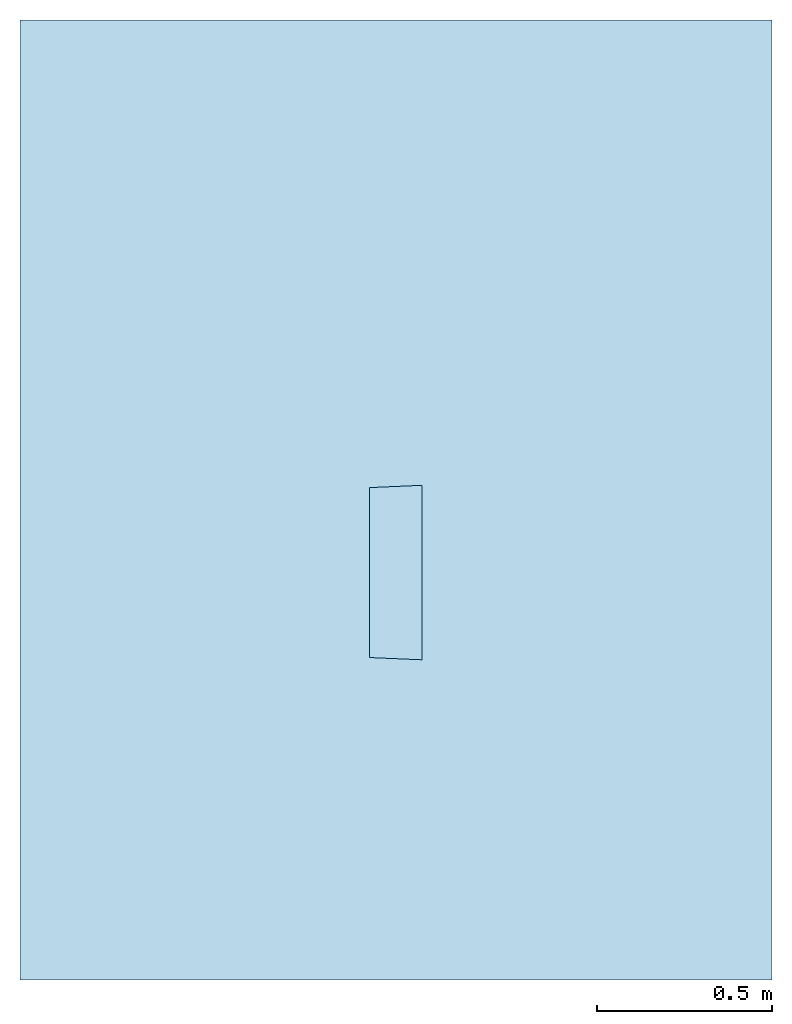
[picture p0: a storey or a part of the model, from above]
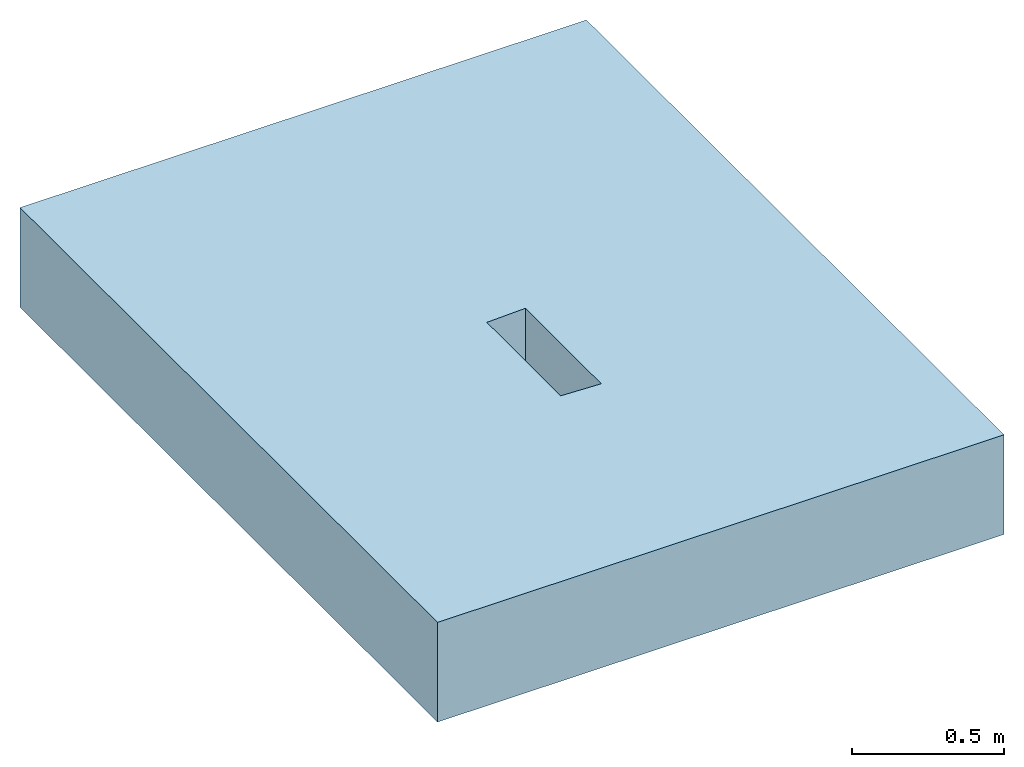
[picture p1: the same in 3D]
Properties of the parts of a building model (IFC2X3)

# File
Description: ViewDefinition [CoordinationView]
File name: 4934 - 7-6m external mitre.ifc
Time: 2013-09-18T16:22:58
Written by: Autodesk Revit 2013
Made in: 20120221_2030(x64)

# IfcProject, Project Number
LongName: Project Name; Phase: Project Status

# IfcSite, Default
RefLatitude: 42, 21, 30, 344238; RefLongitude: -71, -3, -35, -194702; RefElevation: 0 mm

# IfcBuilding
Pset_BuildingCommon - NumberOfStoreys: 2
Other - Project Issue Date: Issue Date; Project Number: Project Number; Client Name: Owner; Project Name: Project Name; Project Status: Project Status; Project Address: Enter address here

# IfcBuildingStorey (2)
Constraints - Elevation Base: 0
Graphics - Symbol: M_Level Head - Circle: M_Level Head - Circle; Line Weight: 1; Line Pattern: Center; Symbol at End 2 Default: yes; Color: 0; Symbol at End 1 Default: no
Dimensions - Computation Height: 0 mm
Identity Data - Building Story: yes; Structural: no
Name | LongName = Name | Elevation (mm) = Constraints, Elevation (mm)
T.O. Fnd. Wall | T.O. Fnd. Wall | -300
Level 1 | Level 1 | 0

# IfcBuildingElementProxy: 4934 - 7-6m external mitre, Civil-Drainage-Channel-ACO-KerbDrain-HB480(amar):4934 - 7-6m external mitre:4934 - 7-6m external mitre:481515
In: T.O. Fnd. Wall
Material: ACO Polymer Concrete.
Other - CreatedBy: www.aco.co.uk; Revision: 1
Green Building Properties - Channel Recyclable: Fully recyclable; Access Cover/Frame Recyclable: N/A; End Cap Recyclable: N/A; End Cap Recycled Material Content: N/A; Access Cover/Frame Recycled Material Content: N/A; Channel Recycled Material Content: 20% minimum
Phasing - Phase Created: Phase 1
Constraints - Level: Level: Level 1; Moves With Nearby Elements: no
Dimensions - Volume: 16451632 mm3; Void Length: 500 mm; Mitre Void End: 355 mm; I/O endcap void depth: 2000 mm; Void Start I/O: 0 mm; Mitre Long end: 499 mm; Void Depth: -2505 mm; Straight Void Start: -2500 mm; Mitre Void Start: 0 mm; Void End I/O: 150 mm; Junction Start: 0 mm; Void Width: 150 mm; Mitre Small End: 486 mm; Junction End: 150 mm; junction void depth: 2000 mm
Pset_BuildingElementProxyCommon - Reference: 4934 - 7-6m external mitre
General - SerialNumber: 0.000000; TagNumber: 0.000000
Identity Data - Installation guidelines: http://www.aco.co.uk/download.php?id=120; OmniClass Number: 23.70.50.24; Product brochure: http://www.aco.co.uk/download.php?id=120; Assembly Description: Rain Water Drainage; Price: POA - contact ACO; Type Comments: ACO KerbDrain HB480 half battered 7-6m external mitre unit 500/487mm long; Maintenance guidelines: http://www.aco.co.uk/download.php?id=120; URL: www.aco.co.uk; e-mail Sales: customersupport@aco.co.uk; Product Code: 4934; Manufacturer: ACO Technologies plc - ACO Water Management Division; Product Page URL: http://www.aco.co.uk/product_detail.php?id=3; OmniClass Title: Rainwater Removal; Model Description: Combined kerb and drainage system; Fax: +44 (0)1462 815895; Telephone: +44 (0)1462 816666; Address: ACO Business Park, Hitchin Road, Shefford, Bedfordshire, United Kingdom SG17 5TE; Model: ACO KerbDrain HB480; e-mail Technical: technical@aco.co.uk; Assembly Code: D2040; Cost: 0
Materials and Finishes - Channel Colour: Grey; End Cap Material: N/A; Access Cover/Frame Colour: N/A; Connection Pipe Material Colour: N/A; Connection Pipe Material: N/A; Channel Material: Vienite® Synthetic Resin Concrete; Access Cover/Frame Finish: N/A; End Cap Colour: N/A; Access Cover/Frame Material: N/A
Construction - Junction channel: no; KDHB480 500_blindunit: no; 25-11m external mitre: no; 7-6m external mitre: yes; RH inlet/outlet end cap: no; RH drop kerb: no; Bus stop kerb: no; RH BS transition kerb: no; Access Unit: no; HB480-500: no; Junction access unit: no; Closing end cap: no; cable loop: no; LH BS transition kerb: no; Centre Stone: no; perforated centre stone: no; LH drop kerb: no; Junction end cap: no; LH inlet/outlet end cap: no; 10-8m external mitre: no; 25-11m internal mitre: no
Data - Drainage Slot Width: 50mm; Connection Pipe O.D: N/A; Hydraulic Performance: http://www.aco.co.uk/download.php?id=120; Product Dimensions: 500/487mm x 150mm x 480mm (LxWxH); Concrete Surround Volume - Load Class A 15 - D 400 - Grass or Asphalt Pavement: N/A; Installation - Concrete Grade: Refer to brochure; Load Class: A 15 - D 400; Invert Depth: 455mm; Concrete Surround Volume - Load Class A 15 - D 400 - Concrete Pavement: N/A; ACO Hydraulic Design Software: http://www.acodesign.co.uk; Channel C.S.A: 0.04m²; Product Standard: BS EN 1433:2002, CE marked, Kitemarked; Product Weight: 36.2 Kg; Drainage Slot Intake area: 14592mm²/m

# IfcOpeningElement: Opening (3)
In: Level 1
Phasing - Phase Created: Phase 1
Dimensions - Area: 5901750 mm2; Perimeter: 9790 mm; Thickness: 400 mm; Volume: 2334474375 mm3
Constraints - Height Offset From Level: 0 mm; Room Bounding: yes; Related to Mass: no; Level: Level: Level 1
Structural - Enable Analytical Model: no; Structural: no
Construction - Function: 0; Default Thickness: 400 mm
Analytical Properties - Absorptance: 0.1; Thermal mass: 543920; Heat Transfer Coefficient (U): 2.0925; Thermal Resistance (R): 0.477897; Roughness: 1
Graphics - Coarse Scale Fill Color: 0
Materials and Finishes - Structural Material: Earth

# IfcSlab: Floor:Generic Floor - 400mm, Floor:Generic Floor - 400mm:136426
In: Level 1
PredefinedType: FLOOR; Material: Earth 400 mm
Phasing - Phase Created: Phase 1
Dimensions - Area: 5901750 mm2; Perimeter: 9790 mm; Thickness: 400 mm; Volume: 2334474375 mm3
Constraints - Height Offset From Level: 0 mm; Room Bounding: yes; Related to Mass: no; Level: Level: Level 1
Structural - Enable Analytical Model: no; Structural: no
Pset_SlabCommon - Reference: Generic Floor - 400mm; IsExternal: no; LoadBearing: yes
Construction - Function: 0; Default Thickness: 400 mm
Analytical Properties - Absorptance: 0.1; Thermal mass: 543920; Heat Transfer Coefficient (U): 2.0925; Thermal Resistance (R): 0.477897; Roughness: 1
Graphics - Coarse Scale Fill Color: 0
Materials and Finishes - Structural Material: Earth
